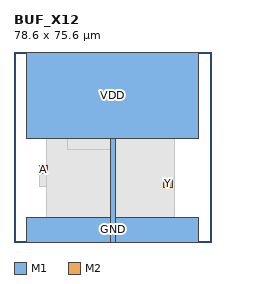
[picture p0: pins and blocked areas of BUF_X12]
MACRO BUF_X12
  CLASS CORE ;
  ORIGIN 0 0 ;
  SIZE 78.600 BY 75.600 ;
  SYMMETRY X Y ;
  SITE TR1um_access_site ;
  PIN VDD
    DIRECTION INOUT ;
    USE POWER ;
    PORT
      LAYER M1 ;
        RECT 38.400 0.000 40.200 41.000 ;
      LAYER M1 ;
        RECT 5.000 41.000 73.600 75.600 ;
    END
  END VDD
  PIN GND
    DIRECTION INOUT ;
    USE GROUND ;
    PORT
      LAYER M1 ;
        RECT 5.000 0.000 73.600 9.800 ;
    END
  END GND
  PIN A
    DIRECTION INPUT ;
    USE SIGNAL ;
    PORT
      LAYER M2 ;
        RECT 10.100 27.100 13.500 30.500 ;
    END
  END A
  PIN Y
    DIRECTION OUTPUT ;
    USE SIGNAL ;
    PORT
      LAYER M2 ;
        RECT 59.600 21.600 63.000 25.000 ;
    END
  END Y
  OBS
    LAYER M1 ;
      RECT 21.100 6.400 38.400 14.000 ;
    LAYER M1 ;
      RECT 24.600 15.900 38.400 18.500 ;
    LAYER M1 ;
      RECT 10.100 22.000 14.500 30.500 ;
    LAYER M1 ;
      RECT 24.400 32.300 38.400 34.900 ;
    LAYER M1 ;
      RECT 40.200 15.900 59.500 34.900 ;
    LAYER M1 ;
      RECT 13.100 6.400 38.400 51.200 ;
    LAYER M1 ;
      RECT 21.100 36.800 39.700 51.200 ;
    LAYER M1 ;
      RECT 40.200 6.400 63.700 51.200 ;
    LAYER V1 ;
      RECT 60.600 22.600 62.000 24.000 ;
    LAYER V1 ;
      RECT 11.100 28.100 12.500 29.500 ;
  END
END BUF_X12
